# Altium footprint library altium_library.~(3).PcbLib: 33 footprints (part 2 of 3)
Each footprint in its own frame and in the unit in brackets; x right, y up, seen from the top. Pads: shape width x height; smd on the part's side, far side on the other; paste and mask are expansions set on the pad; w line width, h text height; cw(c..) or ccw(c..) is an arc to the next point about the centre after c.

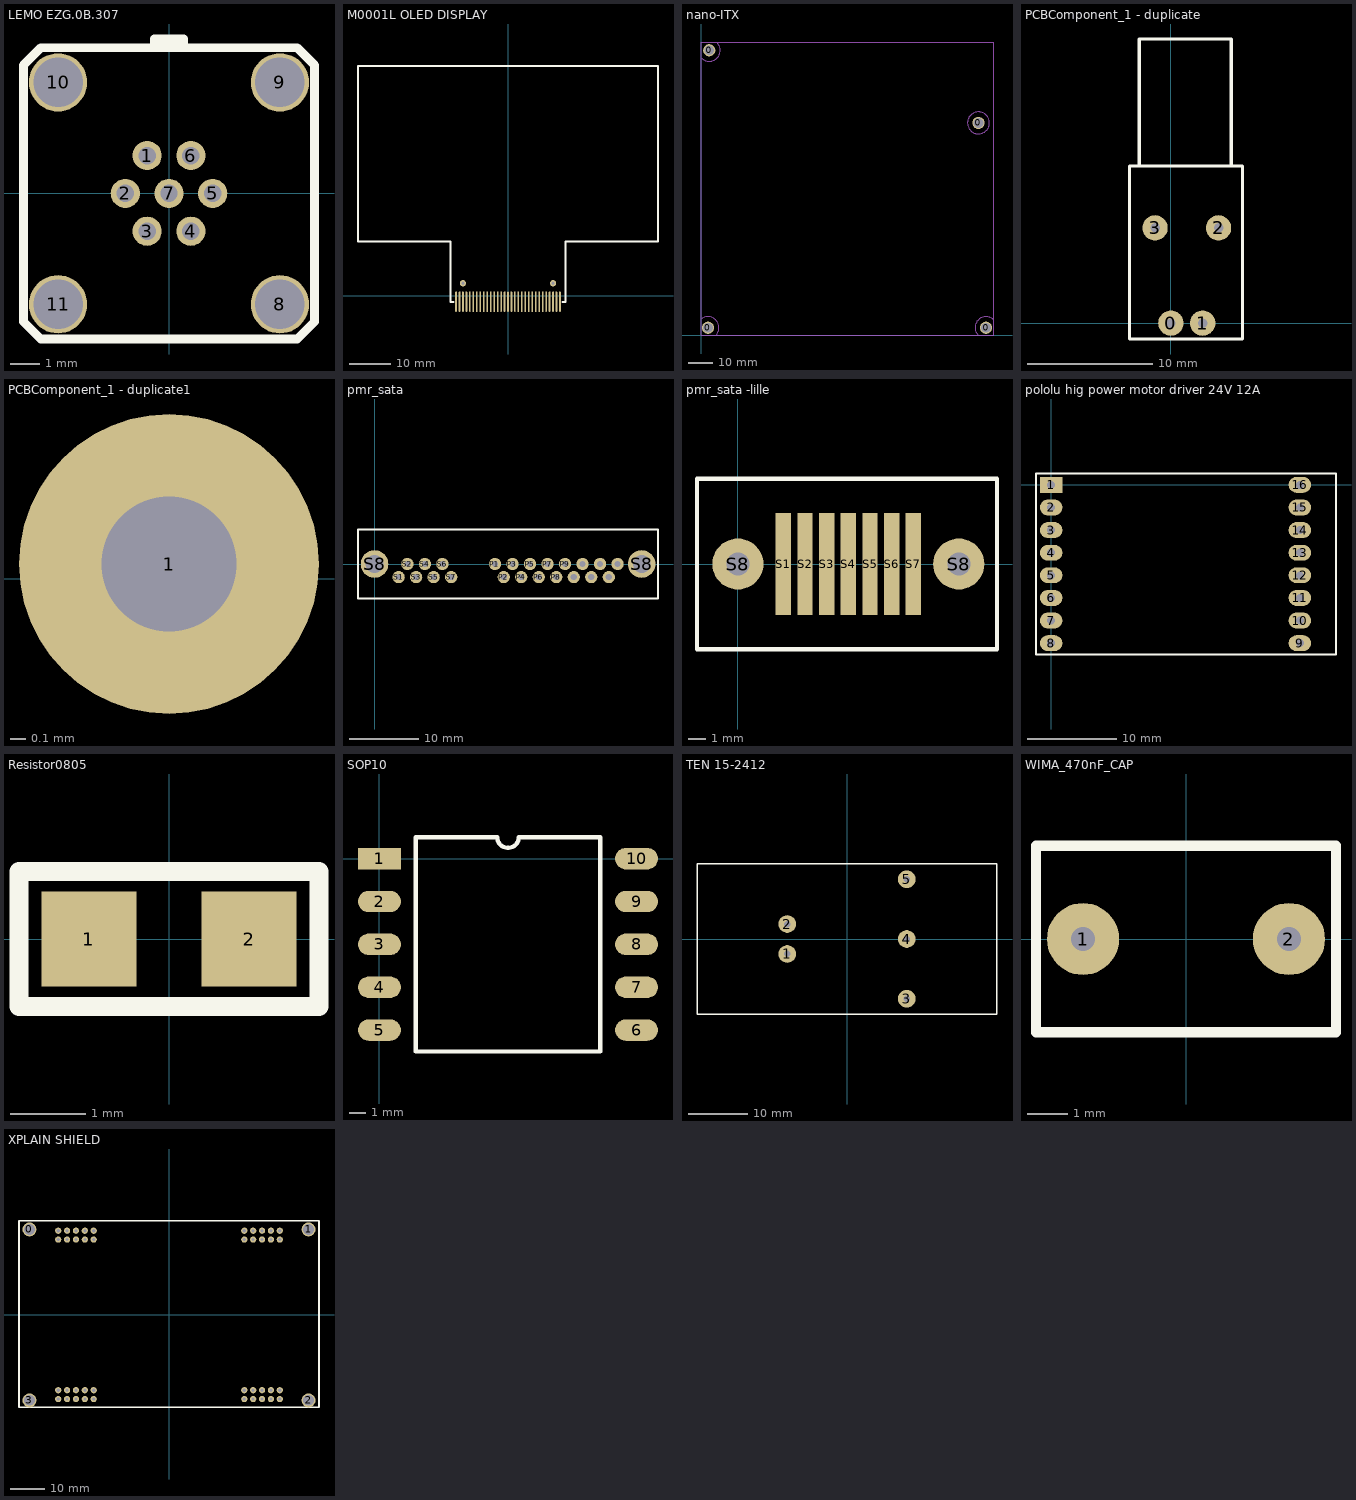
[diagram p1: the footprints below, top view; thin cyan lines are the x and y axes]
## LEMO EZG.0B.307 [mm]
height 15
pads (11):
  round 1 hole 0.6: 1(-0.75,1.299) 2(-1.5,0) 3(-0.75,-1.299) 4(0.75,-1.299) 5(1.5,0) 6(0.75,1.299) 7(0,0)
  round 2 hole 1.7: 8(3.81,-3.81) 9(3.81,3.81) 10(-3.81,3.81) 11(-3.81,-3.81)
Top Overlay:
  lines w0.305: -0.5,5 -0.5,5.3 0.5,5.3 0.5,5 ; -5,-4.4 -4.4,-5 4.4,-5 5,-4.4 5,4.4 4.4,5 -4.4,5 -5,4.4 -5,-4.4

## M0001L OLED DISPLAY [mm]
pads (33):
  oval 0.4x5 smd: 1(-12.675,-1.5) 2(-11.83,-1.5) 3(-10.985,-1.5) 4(-10.14,-1.5) 5(-9.295,-1.5) 6(-8.45,-1.5) 7(-7.605,-1.5) 8(-6.76,-1.5) 9(-5.915,-1.5) 10(-5.07,-1.5) 11(-4.225,-1.5) 12(-3.38,-1.5) 13(-2.535,-1.5) 14(-1.69,-1.5) 15(-0.845,-1.5) 16(0,-1.5) 17(0.845,-1.5) 18(1.69,-1.5) 19(2.535,-1.5) 20(3.38,-1.5) 21(4.225,-1.5) 22(5.07,-1.5) 23(5.915,-1.5) 24(6.76,-1.5) 25(7.605,-1.5) 26(8.45,-1.5) 27(9.295,-1.5) 28(10.14,-1.5) 29(10.985,-1.5) 30(11.83,-1.5) 31(12.675,-1.5)
  round 1.524 hole 0.762: 40(-11,3) 41(11,3)
Top Overlay:
  lines w0.508: -13.3,-1.6 -14,-1.6 -14,13.2 -36.6,13.2 -36.6,56 36.6,56 36.6,13.2 14,13.2 14,-1.6 13.3,-1.6

## nano-ITX [mm] "form factor + holes nano itx"
pads (4):
  round 5 hole 4: 0(2.75,3) 0(3.26,116.76) 0(113.65,86.98) 0(116.76,3)
Mechanical 1:
  circle w0.508: c113.65,86.98 r4.5
  lines w0.254: 0,0 120,0 120,120 0,120 0,0
  lines w0.508: 0.18,113.479 ccw(c3.26,116.76) 6.58,119.798 ; 0.191,6.701 cw(c2.75,3) 6.294,0.227 ; 113.28,0.147 cw(c116.76,3) 119.753,6.36

## PCBComponent_1 [mil]

## PCBComponent_1 - duplicate [mil]
pads (4):
  round 80 hole 30: 0(0,0) 1(100,0) 2(150,300) 3(-50,300)
Top Overlay:
  lines w10: -100,495 -100,895 190,895 190,495 ; -130,-50 -130,495 225,495 225,-50 -130,-50

## PCBComponent_1 - duplicate1 [mm]
pads (1):
  round 2 hole 0.9: 1(-3.9,0.1)

## PCBComponent_1 - duplicate2 [mil]

## PCBComponent_1 - duplicate3 [mil]

## pmr_sata [mm]
pads (24):
  round 1.778 hole 0.9: P1(17.46,0) P2(18.73,-1.9) P3(20,0) P4(21.27,-1.9) P5(22.54,0) P6(23.81,-1.9) P7(25.08,0) P8(26.35,-1.9) P9(27.62,0) P10(28.89,-1.9) P11(30.16,0) P12(31.43,-1.9) P13(32.7,0) P14(33.97,-1.9) P15(35.24,0) S1(3.49,-1.9) S2(4.76,0) S3(6.03,-1.9) S4(7.3,0) S5(8.57,-1.9) S6(9.84,0) S7(11.11,-1.9)
  round 4 hole 2.6: S8(0,0) S8(38.74,0)
Top Overlay:
  lines w0.254: -2.4,-5 -2.4,5 41.1,5 41.1,-5 -2.4,-5

## pmr_sata -lille [mm]
pads (9):
  rect 0.9x6 smd: S1(2.67,0) S2(3.94,0) S3(5.21,0) S4(6.48,0) S5(7.75,0) S6(9.02,0) S7(10.29,0)
  round 3 hole 1.35: S8(0,0) S8(12.96,0)
Top Overlay:
  lines w0.254: -2.4,-5 15.2,-5 15.2,5 -2.4,5 -2.4,-5

## pololu hig power motor driver 24V 12A [mil]
pads (16):
  rect 100x70 hole 35: 1(0,0)
  oval 100x70 hole 35: 2(0,-100) 3(0,-200) 4(0,-300) 5(0,-400) 6(0,-500) 7(0,-600) 8(0,-700) 9(1100,-700) 10(1100,-600) 11(1100,-500) 12(1100,-400) 13(1100,-300) 14(1100,-200) 15(1100,-100) 16(1100,0)
Top Overlay:
  lines w10: 575,50 1259.84,50 1259.84,-750 -66.93,-750 -66.93,50 582.68,50

## Resistor0805 [mil]
pads (2):
  rect 50x50 smd: 1(-42,0) 2(42,0)
Top Overlay:
  lines w10: -78.74,-35.43 -78.74,-26.74 -78.74,35.43 78.74,35.43 78.74,-35.43 -78.74,-35.43

## SOP10 [mil]
pads (10):
  rect 100x50 smd: 1(0,0)
  oval 100x50 smd: 2(0,-100) 3(0,-200) 4(0,-300) 5(0,-400) 6(600,-400) 7(600,-300) 8(600,-200) 9(600,-100) 10(600,0)
Top Overlay:
  lines w10: 85,-450 515,-450 515,50 325,50 cw(c300,50) 275,50 85,50 85,-450

## TEN 15-2412 [mm]
pads (5):
  round 3 hole 1.1: 1(-10.16,-2.54) 2(-10.16,2.54) 3(10.16,-10.16) 4(10.16,0) 5(10.16,10.16)
Top Overlay:
  lines w0.254: 19.5,12.8 25.5,12.8 25.5,-12.8 -25.5,-12.8 -25.5,12.8 1.2,12.8 20.6,12.8

## WIMA_470nF_CAP [mil]
pads (2):
  round 70 hole 23.62: 1(-100,0) 2(100,0)
Top Overlay:
  lines w10: -145.67,-90.55 -145.67,90.55 145.67,90.55 145.67,-90.55 -145.67,-90.55

## XPLAIN SHIELD [mil]
pads (44):
  round 157.48 hole 122.05: 0(-1574.8,964.57) 1(1574.8,964.57) 2(1574.8,-964.57) 3(-1574.8,-964.57)
  round 70 hole 35.43: 11(850,850) 12(850,950) 13(950,850) 14(950,950) 15(1050,850) 16(1050,950) 17(1150,850) 18(1150,950) 19(1250,850) 20(1250,950) 21(850,-950) 22(850,-850) 23(950,-950) 24(950,-850) 25(1050,-950) 26(1050,-850) 27(1150,-950) 28(1150,-850) 29(1250,-950) 30(1250,-850) 31(-1250,-950) 32(-1250,-850) 33(-1150,-950) 34(-1150,-850) 35(-1050,-950) 36(-1050,-850) 37(-950,-950) 38(-950,-850) 39(-850,-950) 40(-850,-850) 41(-1250,850) 42(-1250,950) 43(-1150,850) 44(-1150,950) 45(-1050,850) 46(-1050,950) 47(-950,850) 48(-950,950) 49(-850,850) 50(-850,950)
Top Overlay:
  lines w20: -1692.91,-1043.31 1692.91,-1043.31 1692.91,1062.99 -1692.91,1062.99 -1692.91,-1043.31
